VERSION 5.7 ;
  NOWIREEXTENSIONATPIN ON ;
  DIVIDERCHAR "/" ;
  BUSBITCHARS "[]" ;
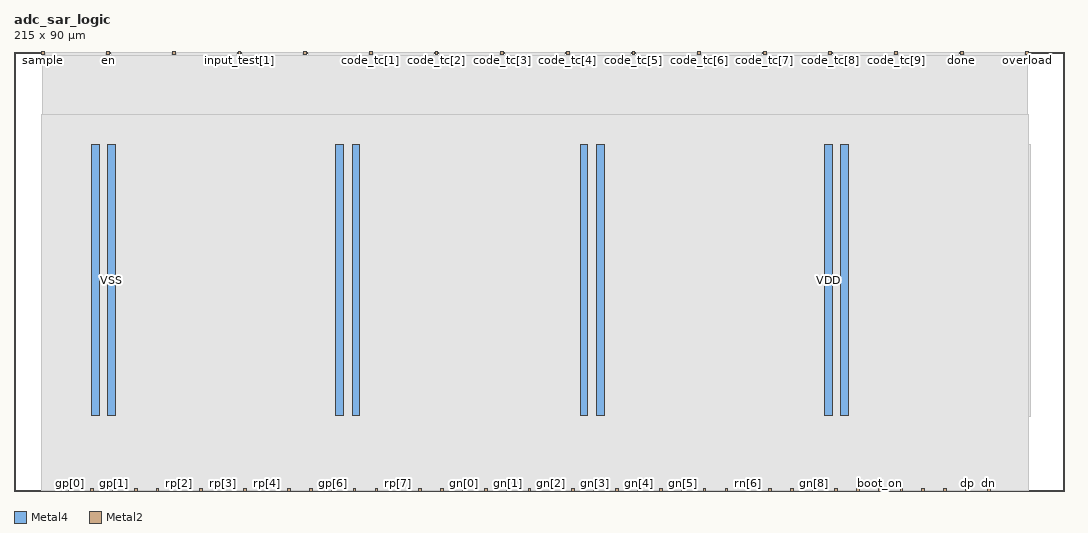
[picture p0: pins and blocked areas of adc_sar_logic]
MACRO adc_sar_logic
  CLASS BLOCK ;
  FOREIGN adc_sar_logic ;
  ORIGIN 0.000 0.000 ;
  SIZE 215.000 BY 90.000 ;
  PIN VDD
    DIRECTION INOUT ;
    USE POWER ;
    PORT
      LAYER Metal4 ;
        RECT 15.920 15.380 17.520 70.860 ;
    END
    PORT
      LAYER Metal4 ;
        RECT 65.920 15.380 67.520 70.860 ;
    END
    PORT
      LAYER Metal4 ;
        RECT 115.920 15.380 117.520 70.860 ;
    END
    PORT
      LAYER Metal4 ;
        RECT 165.920 15.380 167.520 70.860 ;
    END
  END VDD
  PIN VSS
    DIRECTION INOUT ;
    USE GROUND ;
    PORT
      LAYER Metal4 ;
        RECT 19.220 15.380 20.820 70.860 ;
    END
    PORT
      LAYER Metal4 ;
        RECT 69.220 15.380 70.820 70.860 ;
    END
    PORT
      LAYER Metal4 ;
        RECT 119.220 15.380 120.820 70.860 ;
    END
    PORT
      LAYER Metal4 ;
        RECT 169.220 15.380 170.820 70.860 ;
    END
  END VSS
  PIN boot_on
    DIRECTION OUTPUT ;
    USE SIGNAL ;
    ANTENNAGATEAREA 0.898000 ;
    ANTENNADIFFAREA 0.983200 ;
    PORT
      LAYER Metal2 ;
        RECT 176.960 0.000 177.520 0.560 ;
    END
  END boot_on
  PIN boot_onb
    DIRECTION OUTPUT ;
    USE SIGNAL ;
    ANTENNADIFFAREA 0.748000 ;
    PORT
      LAYER Metal2 ;
        RECT 181.440 0.000 182.000 0.560 ;
    END
  END boot_onb
  PIN cmp_clk
    DIRECTION OUTPUT ;
    USE SIGNAL ;
    ANTENNADIFFAREA 4.408000 ;
    PORT
      LAYER Metal2 ;
        RECT 172.480 0.000 173.040 0.560 ;
    END
  END cmp_clk
  PIN code_tc[0]
    DIRECTION OUTPUT ;
    USE SIGNAL ;
    ANTENNADIFFAREA 0.893200 ;
    PORT
      LAYER Metal2 ;
        RECT 59.360 89.440 59.920 90.000 ;
    END
  END code_tc[0]
  PIN code_tc[1]
    DIRECTION OUTPUT ;
    USE SIGNAL ;
    ANTENNADIFFAREA 0.893200 ;
    PORT
      LAYER Metal2 ;
        RECT 72.800 89.440 73.360 90.000 ;
    END
  END code_tc[1]
  PIN code_tc[2]
    DIRECTION OUTPUT ;
    USE SIGNAL ;
    ANTENNADIFFAREA 0.893200 ;
    PORT
      LAYER Metal2 ;
        RECT 86.240 89.440 86.800 90.000 ;
    END
  END code_tc[2]
  PIN code_tc[3]
    DIRECTION OUTPUT ;
    USE SIGNAL ;
    ANTENNADIFFAREA 0.893200 ;
    PORT
      LAYER Metal2 ;
        RECT 99.680 89.440 100.240 90.000 ;
    END
  END code_tc[3]
  PIN code_tc[4]
    DIRECTION OUTPUT ;
    USE SIGNAL ;
    ANTENNADIFFAREA 0.893200 ;
    PORT
      LAYER Metal2 ;
        RECT 113.120 89.440 113.680 90.000 ;
    END
  END code_tc[4]
  PIN code_tc[5]
    DIRECTION OUTPUT ;
    USE SIGNAL ;
    ANTENNADIFFAREA 0.893200 ;
    PORT
      LAYER Metal2 ;
        RECT 126.560 89.440 127.120 90.000 ;
    END
  END code_tc[5]
  PIN code_tc[6]
    DIRECTION OUTPUT ;
    USE SIGNAL ;
    ANTENNADIFFAREA 0.893200 ;
    PORT
      LAYER Metal2 ;
        RECT 140.000 89.440 140.560 90.000 ;
    END
  END code_tc[6]
  PIN code_tc[7]
    DIRECTION OUTPUT ;
    USE SIGNAL ;
    ANTENNADIFFAREA 0.893200 ;
    PORT
      LAYER Metal2 ;
        RECT 153.440 89.440 154.000 90.000 ;
    END
  END code_tc[7]
  PIN code_tc[8]
    DIRECTION OUTPUT ;
    USE SIGNAL ;
    ANTENNADIFFAREA 0.893200 ;
    PORT
      LAYER Metal2 ;
        RECT 166.880 89.440 167.440 90.000 ;
    END
  END code_tc[8]
  PIN code_tc[9]
    DIRECTION OUTPUT ;
    USE SIGNAL ;
    ANTENNADIFFAREA 0.893200 ;
    PORT
      LAYER Metal2 ;
        RECT 180.320 89.440 180.880 90.000 ;
    END
  END code_tc[9]
  PIN dn
    DIRECTION INPUT ;
    USE SIGNAL ;
    ANTENNAGATEAREA 1.882500 ;
    PORT
      LAYER Metal2 ;
        RECT 199.360 0.000 199.920 0.560 ;
    END
  END dn
  PIN done
    DIRECTION OUTPUT ;
    USE SIGNAL ;
    ANTENNAGATEAREA 9.358500 ;
    ANTENNADIFFAREA 0.893200 ;
    PORT
      LAYER Metal2 ;
        RECT 193.760 89.440 194.320 90.000 ;
    END
  END done
  PIN dp
    DIRECTION INPUT ;
    USE SIGNAL ;
    ANTENNAGATEAREA 2.939500 ;
    PORT
      LAYER Metal2 ;
        RECT 194.880 0.000 195.440 0.560 ;
    END
  END dp
  PIN en
    DIRECTION INPUT ;
    USE SIGNAL ;
    ANTENNAGATEAREA 17.596500 ;
    PORT
      LAYER Metal2 ;
        RECT 19.040 89.440 19.600 90.000 ;
    END
  END en
  PIN gn[0]
    DIRECTION OUTPUT ;
    USE SIGNAL ;
    ANTENNADIFFAREA 0.897600 ;
    PORT
      LAYER Metal2 ;
        RECT 91.840 0.000 92.400 0.560 ;
    END
  END gn[0]
  PIN gn[1]
    DIRECTION OUTPUT ;
    USE SIGNAL ;
    ANTENNADIFFAREA 0.897600 ;
    PORT
      LAYER Metal2 ;
        RECT 100.800 0.000 101.360 0.560 ;
    END
  END gn[1]
  PIN gn[2]
    DIRECTION OUTPUT ;
    USE SIGNAL ;
    ANTENNADIFFAREA 0.897600 ;
    PORT
      LAYER Metal2 ;
        RECT 109.760 0.000 110.320 0.560 ;
    END
  END gn[2]
  PIN gn[3]
    DIRECTION OUTPUT ;
    USE SIGNAL ;
    ANTENNADIFFAREA 0.897600 ;
    PORT
      LAYER Metal2 ;
        RECT 118.720 0.000 119.280 0.560 ;
    END
  END gn[3]
  PIN gn[4]
    DIRECTION OUTPUT ;
    USE SIGNAL ;
    ANTENNADIFFAREA 0.897600 ;
    PORT
      LAYER Metal2 ;
        RECT 127.680 0.000 128.240 0.560 ;
    END
  END gn[4]
  PIN gn[5]
    DIRECTION OUTPUT ;
    USE SIGNAL ;
    ANTENNADIFFAREA 0.897600 ;
    PORT
      LAYER Metal2 ;
        RECT 136.640 0.000 137.200 0.560 ;
    END
  END gn[5]
  PIN gn[6]
    DIRECTION OUTPUT ;
    USE SIGNAL ;
    ANTENNADIFFAREA 0.897600 ;
    PORT
      LAYER Metal2 ;
        RECT 145.600 0.000 146.160 0.560 ;
    END
  END gn[6]
  PIN gn[7]
    DIRECTION OUTPUT ;
    USE SIGNAL ;
    ANTENNADIFFAREA 1.276000 ;
    PORT
      LAYER Metal2 ;
        RECT 154.560 0.000 155.120 0.560 ;
    END
  END gn[7]
  PIN gn[8]
    DIRECTION OUTPUT ;
    USE SIGNAL ;
    ANTENNADIFFAREA 0.897600 ;
    PORT
      LAYER Metal2 ;
        RECT 163.520 0.000 164.080 0.560 ;
    END
  END gn[8]
  PIN gp[0]
    DIRECTION OUTPUT ;
    USE SIGNAL ;
    ANTENNADIFFAREA 0.897600 ;
    PORT
      LAYER Metal2 ;
        RECT 11.200 0.000 11.760 0.560 ;
    END
  END gp[0]
  PIN gp[1]
    DIRECTION OUTPUT ;
    USE SIGNAL ;
    ANTENNADIFFAREA 0.897600 ;
    PORT
      LAYER Metal2 ;
        RECT 20.160 0.000 20.720 0.560 ;
    END
  END gp[1]
  PIN gp[2]
    DIRECTION OUTPUT ;
    USE SIGNAL ;
    ANTENNADIFFAREA 0.897600 ;
    PORT
      LAYER Metal2 ;
        RECT 29.120 0.000 29.680 0.560 ;
    END
  END gp[2]
  PIN gp[3]
    DIRECTION OUTPUT ;
    USE SIGNAL ;
    ANTENNADIFFAREA 0.897600 ;
    PORT
      LAYER Metal2 ;
        RECT 38.080 0.000 38.640 0.560 ;
    END
  END gp[3]
  PIN gp[4]
    DIRECTION OUTPUT ;
    USE SIGNAL ;
    ANTENNADIFFAREA 0.897600 ;
    PORT
      LAYER Metal2 ;
        RECT 47.040 0.000 47.600 0.560 ;
    END
  END gp[4]
  PIN gp[5]
    DIRECTION OUTPUT ;
    USE SIGNAL ;
    ANTENNADIFFAREA 0.897600 ;
    PORT
      LAYER Metal2 ;
        RECT 56.000 0.000 56.560 0.560 ;
    END
  END gp[5]
  PIN gp[6]
    DIRECTION OUTPUT ;
    USE SIGNAL ;
    ANTENNADIFFAREA 0.897600 ;
    PORT
      LAYER Metal2 ;
        RECT 64.960 0.000 65.520 0.560 ;
    END
  END gp[6]
  PIN gp[7]
    DIRECTION OUTPUT ;
    USE SIGNAL ;
    ANTENNADIFFAREA 1.276000 ;
    PORT
      LAYER Metal2 ;
        RECT 73.920 0.000 74.480 0.560 ;
    END
  END gp[7]
  PIN gp[8]
    DIRECTION OUTPUT ;
    USE SIGNAL ;
    ANTENNADIFFAREA 0.897600 ;
    PORT
      LAYER Metal2 ;
        RECT 82.880 0.000 83.440 0.560 ;
    END
  END gp[8]
  PIN input_test[0]
    DIRECTION INPUT ;
    USE SIGNAL ;
    ANTENNAGATEAREA 4.937500 ;
    PORT
      LAYER Metal2 ;
        RECT 32.480 89.440 33.040 90.000 ;
    END
  END input_test[0]
  PIN input_test[1]
    DIRECTION INPUT ;
    USE SIGNAL ;
    ANTENNAGATEAREA 2.736000 ;
    PORT
      LAYER Metal2 ;
        RECT 45.920 89.440 46.480 90.000 ;
    END
  END input_test[1]
  PIN lsb_rst
    DIRECTION OUTPUT ;
    USE SIGNAL ;
    ANTENNAGATEAREA 0.396000 ;
    ANTENNADIFFAREA 0.748000 ;
    PORT
      LAYER Metal2 ;
        RECT 190.400 0.000 190.960 0.560 ;
    END
  END lsb_rst
  PIN overload
    DIRECTION OUTPUT ;
    USE SIGNAL ;
    ANTENNADIFFAREA 0.893200 ;
    PORT
      LAYER Metal2 ;
        RECT 207.200 89.440 207.760 90.000 ;
    END
  END overload
  PIN rn[0]
    DIRECTION OUTPUT ;
    USE SIGNAL ;
    ANTENNAGATEAREA 1.054000 ;
    ANTENNADIFFAREA 0.748000 ;
    PORT
      LAYER Metal2 ;
        RECT 96.320 0.000 96.880 0.560 ;
    END
  END rn[0]
  PIN rn[1]
    DIRECTION OUTPUT ;
    USE SIGNAL ;
    ANTENNAGATEAREA 1.054000 ;
    ANTENNADIFFAREA 0.748000 ;
    PORT
      LAYER Metal2 ;
        RECT 105.280 0.000 105.840 0.560 ;
    END
  END rn[1]
  PIN rn[2]
    DIRECTION OUTPUT ;
    USE SIGNAL ;
    ANTENNAGATEAREA 1.054000 ;
    ANTENNADIFFAREA 0.748000 ;
    PORT
      LAYER Metal2 ;
        RECT 114.240 0.000 114.800 0.560 ;
    END
  END rn[2]
  PIN rn[3]
    DIRECTION OUTPUT ;
    USE SIGNAL ;
    ANTENNAGATEAREA 1.054000 ;
    ANTENNADIFFAREA 0.748000 ;
    PORT
      LAYER Metal2 ;
        RECT 123.200 0.000 123.760 0.560 ;
    END
  END rn[3]
  PIN rn[4]
    DIRECTION OUTPUT ;
    USE SIGNAL ;
    ANTENNAGATEAREA 1.054000 ;
    ANTENNADIFFAREA 0.748000 ;
    PORT
      LAYER Metal2 ;
        RECT 132.160 0.000 132.720 0.560 ;
    END
  END rn[4]
  PIN rn[5]
    DIRECTION OUTPUT ;
    USE SIGNAL ;
    ANTENNAGATEAREA 1.054000 ;
    ANTENNADIFFAREA 0.748000 ;
    PORT
      LAYER Metal2 ;
        RECT 141.120 0.000 141.680 0.560 ;
    END
  END rn[5]
  PIN rn[6]
    DIRECTION OUTPUT ;
    USE SIGNAL ;
    ANTENNAGATEAREA 1.054000 ;
    ANTENNADIFFAREA 0.748000 ;
    PORT
      LAYER Metal2 ;
        RECT 150.080 0.000 150.640 0.560 ;
    END
  END rn[6]
  PIN rn[7]
    DIRECTION OUTPUT ;
    USE SIGNAL ;
    ANTENNADIFFAREA 1.145600 ;
    PORT
      LAYER Metal2 ;
        RECT 159.040 0.000 159.600 0.560 ;
    END
  END rn[7]
  PIN rn[8]
    DIRECTION OUTPUT ;
    USE SIGNAL ;
    ANTENNAGATEAREA 1.057000 ;
    ANTENNADIFFAREA 0.748000 ;
    PORT
      LAYER Metal2 ;
        RECT 168.000 0.000 168.560 0.560 ;
    END
  END rn[8]
  PIN rp[0]
    DIRECTION OUTPUT ;
    USE SIGNAL ;
    ANTENNAGATEAREA 1.054000 ;
    ANTENNADIFFAREA 0.748000 ;
    PORT
      LAYER Metal2 ;
        RECT 15.680 0.000 16.240 0.560 ;
    END
  END rp[0]
  PIN rp[1]
    DIRECTION OUTPUT ;
    USE SIGNAL ;
    ANTENNAGATEAREA 1.054000 ;
    ANTENNADIFFAREA 0.748000 ;
    PORT
      LAYER Metal2 ;
        RECT 24.640 0.000 25.200 0.560 ;
    END
  END rp[1]
  PIN rp[2]
    DIRECTION OUTPUT ;
    USE SIGNAL ;
    ANTENNAGATEAREA 1.054000 ;
    ANTENNADIFFAREA 0.748000 ;
    PORT
      LAYER Metal2 ;
        RECT 33.600 0.000 34.160 0.560 ;
    END
  END rp[2]
  PIN rp[3]
    DIRECTION OUTPUT ;
    USE SIGNAL ;
    ANTENNAGATEAREA 1.054000 ;
    ANTENNADIFFAREA 0.748000 ;
    PORT
      LAYER Metal2 ;
        RECT 42.560 0.000 43.120 0.560 ;
    END
  END rp[3]
  PIN rp[4]
    DIRECTION OUTPUT ;
    USE SIGNAL ;
    ANTENNAGATEAREA 1.054000 ;
    ANTENNADIFFAREA 0.748000 ;
    PORT
      LAYER Metal2 ;
        RECT 51.520 0.000 52.080 0.560 ;
    END
  END rp[4]
  PIN rp[5]
    DIRECTION OUTPUT ;
    USE SIGNAL ;
    ANTENNAGATEAREA 1.054000 ;
    ANTENNADIFFAREA 0.748000 ;
    PORT
      LAYER Metal2 ;
        RECT 60.480 0.000 61.040 0.560 ;
    END
  END rp[5]
  PIN rp[6]
    DIRECTION OUTPUT ;
    USE SIGNAL ;
    ANTENNAGATEAREA 1.054000 ;
    ANTENNADIFFAREA 0.748000 ;
    PORT
      LAYER Metal2 ;
        RECT 69.440 0.000 70.000 0.560 ;
    END
  END rp[6]
  PIN rp[7]
    DIRECTION OUTPUT ;
    USE SIGNAL ;
    ANTENNADIFFAREA 1.145600 ;
    PORT
      LAYER Metal2 ;
        RECT 78.400 0.000 78.960 0.560 ;
    END
  END rp[7]
  PIN rp[8]
    DIRECTION OUTPUT ;
    USE SIGNAL ;
    ANTENNAGATEAREA 2.577500 ;
    ANTENNADIFFAREA 0.748000 ;
    PORT
      LAYER Metal2 ;
        RECT 87.360 0.000 87.920 0.560 ;
    END
  END rp[8]
  PIN sample
    DIRECTION INPUT ;
    USE SIGNAL ;
    ANTENNAGATEAREA 3.105500 ;
    PORT
      LAYER Metal2 ;
        RECT 5.600 89.440 6.160 90.000 ;
    END
  END sample
  PIN vcm_top
    DIRECTION OUTPUT ;
    USE SIGNAL ;
    ANTENNADIFFAREA 0.830600 ;
    PORT
      LAYER Metal2 ;
        RECT 185.920 0.000 186.480 0.560 ;
    END
  END vcm_top
  OBS
      LAYER Nwell ;
        RECT 6.290 15.250 208.190 70.990 ;
      LAYER Metal1 ;
        RECT 6.720 15.380 207.760 70.860 ;
      LAYER Metal2 ;
        RECT 6.460 89.140 18.740 89.860 ;
        RECT 19.900 89.140 32.180 89.860 ;
        RECT 33.340 89.140 45.620 89.860 ;
        RECT 46.780 89.140 59.060 89.860 ;
        RECT 60.220 89.140 72.500 89.860 ;
        RECT 73.660 89.140 85.940 89.860 ;
        RECT 87.100 89.140 99.380 89.860 ;
        RECT 100.540 89.140 112.820 89.860 ;
        RECT 113.980 89.140 126.260 89.860 ;
        RECT 127.420 89.140 139.700 89.860 ;
        RECT 140.860 89.140 153.140 89.860 ;
        RECT 154.300 89.140 166.580 89.860 ;
        RECT 167.740 89.140 180.020 89.860 ;
        RECT 181.180 89.140 193.460 89.860 ;
        RECT 194.620 89.140 206.900 89.860 ;
        RECT 5.740 0.860 207.620 89.140 ;
        RECT 5.740 0.140 10.900 0.860 ;
        RECT 12.060 0.140 15.380 0.860 ;
        RECT 16.540 0.140 19.860 0.860 ;
        RECT 21.020 0.140 24.340 0.860 ;
        RECT 25.500 0.140 28.820 0.860 ;
        RECT 29.980 0.140 33.300 0.860 ;
        RECT 34.460 0.140 37.780 0.860 ;
        RECT 38.940 0.140 42.260 0.860 ;
        RECT 43.420 0.140 46.740 0.860 ;
        RECT 47.900 0.140 51.220 0.860 ;
        RECT 52.380 0.140 55.700 0.860 ;
        RECT 56.860 0.140 60.180 0.860 ;
        RECT 61.340 0.140 64.660 0.860 ;
        RECT 65.820 0.140 69.140 0.860 ;
        RECT 70.300 0.140 73.620 0.860 ;
        RECT 74.780 0.140 78.100 0.860 ;
        RECT 79.260 0.140 82.580 0.860 ;
        RECT 83.740 0.140 87.060 0.860 ;
        RECT 88.220 0.140 91.540 0.860 ;
        RECT 92.700 0.140 96.020 0.860 ;
        RECT 97.180 0.140 100.500 0.860 ;
        RECT 101.660 0.140 104.980 0.860 ;
        RECT 106.140 0.140 109.460 0.860 ;
        RECT 110.620 0.140 113.940 0.860 ;
        RECT 115.100 0.140 118.420 0.860 ;
        RECT 119.580 0.140 122.900 0.860 ;
        RECT 124.060 0.140 127.380 0.860 ;
        RECT 128.540 0.140 131.860 0.860 ;
        RECT 133.020 0.140 136.340 0.860 ;
        RECT 137.500 0.140 140.820 0.860 ;
        RECT 141.980 0.140 145.300 0.860 ;
        RECT 146.460 0.140 149.780 0.860 ;
        RECT 150.940 0.140 154.260 0.860 ;
        RECT 155.420 0.140 158.740 0.860 ;
        RECT 159.900 0.140 163.220 0.860 ;
        RECT 164.380 0.140 167.700 0.860 ;
        RECT 168.860 0.140 172.180 0.860 ;
        RECT 173.340 0.140 176.660 0.860 ;
        RECT 177.820 0.140 181.140 0.860 ;
        RECT 182.300 0.140 185.620 0.860 ;
        RECT 186.780 0.140 190.100 0.860 ;
        RECT 191.260 0.140 194.580 0.860 ;
        RECT 195.740 0.140 199.060 0.860 ;
        RECT 200.220 0.140 207.620 0.860 ;
      LAYER Metal3 ;
        RECT 5.690 0.140 207.670 77.140 ;
  END
END adc_sar_logic
END LIBRARY

